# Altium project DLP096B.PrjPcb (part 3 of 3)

## Sheet DLP096B_LED_Driver.SchDoc: LED Driver
size 431 x 279 mm; Date: Not shown in title block; ApprovedBy: Not shown in title block; CheckedBy: Not shown in title block; Author: Not shown in title block; CompanyName: Not shown in title block; DrawnBy: A. Whitehead; Engineer: Not shown in title block; Organization: Not shown in title block; Address1: Not shown in title block; Address2: Not shown in title block; Address3: Not shown in title block; Address4: Not shown in title block; DocumentNumber: 9; Revision: Use project parameter SCH_Rev; SheetNumber: 9; SheetTotal: 10; PageSetup: Record=PageOptions¦CenterHorizontal=True¦CenterVertical=True¦PrintScale=1.00¦XCorrection=1.00¦YCorrection=1.00¦PrintKind=0¦BorderSize=5000000¦LeftOffset=0¦BottomOffset=0¦Orientation=2¦PaperLength=1000¦PaperWidth=1000¦Scale=100¦PaperSource=15¦PrintQuality=600¦MediaType=1¦DitherType=10¦PaperKind=Letter¦PrintScaleMode=1

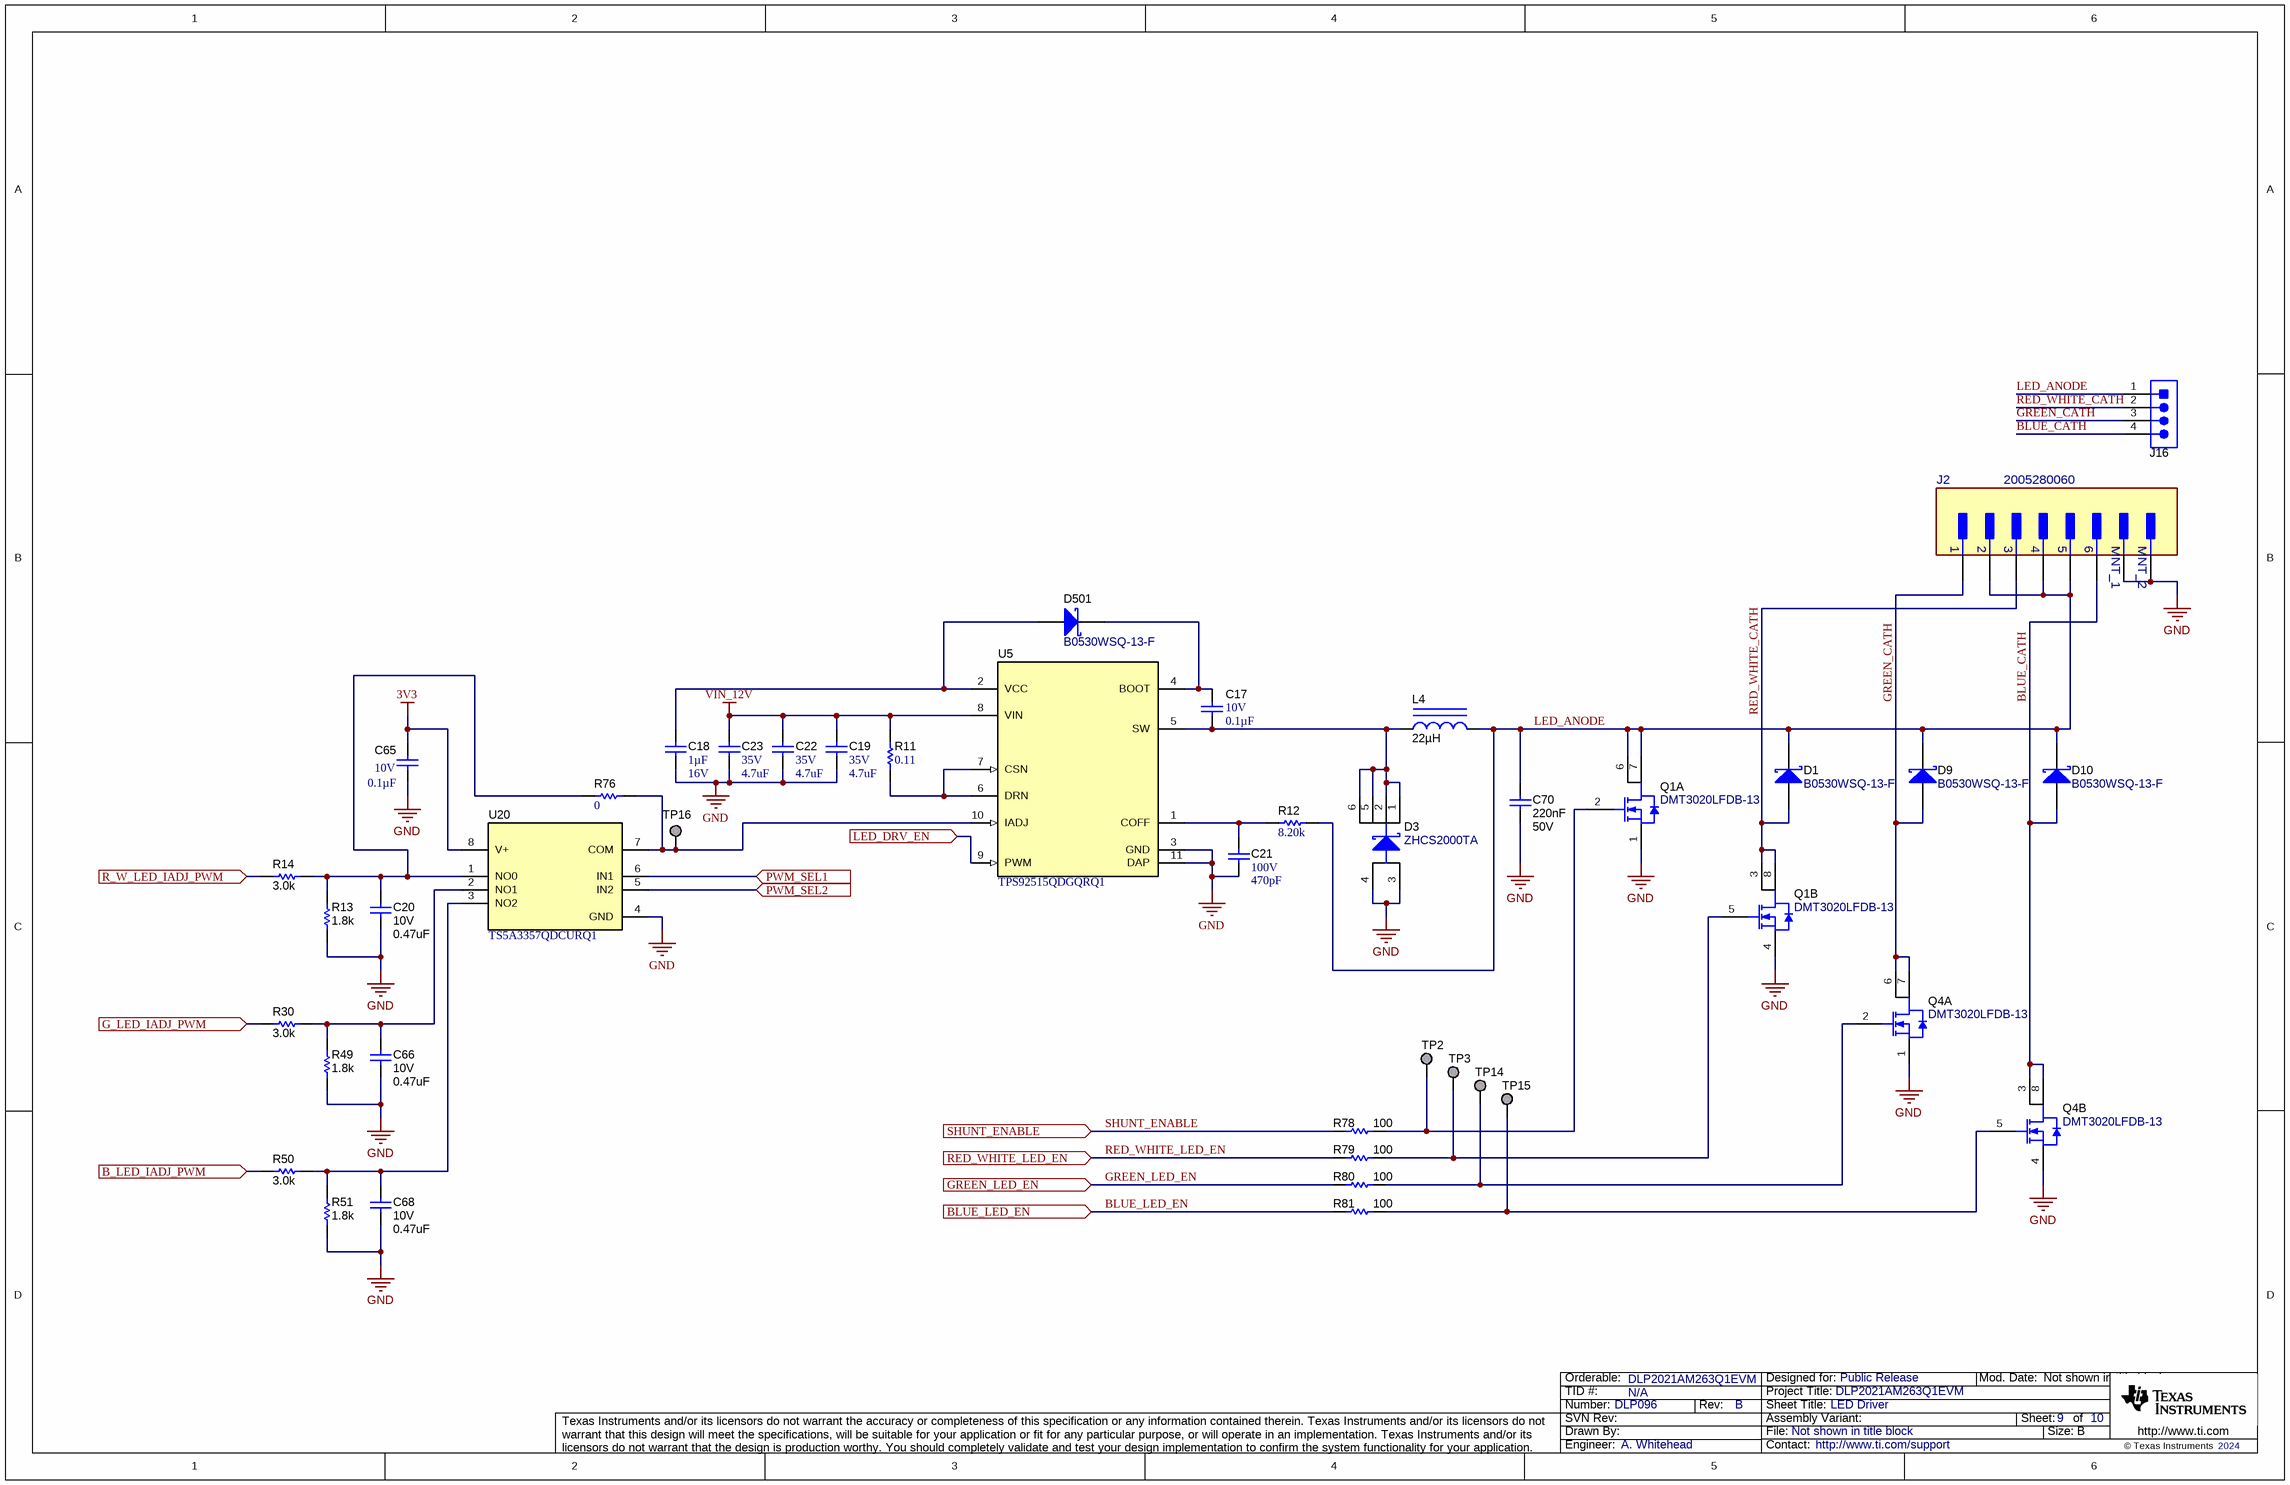
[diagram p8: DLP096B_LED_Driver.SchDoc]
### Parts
C17  VDC_V: 10V  ValueDisplayed: 0.1µF  [0201_033]  (hidden comment: GRM033R61A104KE84D)
C18  Cap_F: 1µF  VDC_V: 16V  [0603]  (hidden comment: CGA3E1X7R1C105K080AC)
C19  VDC_V: 35V  ValueDisplayed: 4.7uF  [0603]  (hidden comment: C1608X5R1V475K080AC)
C20  VDC_V: 10V  ValueDisplayed: 0.47uF  [0402L]  (hidden comment: GRT155R71A474KE01D)
C21  VDC_V: 100V  ValueDisplayed: 470pF  [0603]  (hidden comment: C1608C0G2A471J)
C22  VDC_V: 35V  ValueDisplayed: 4.7uF  [0603]  (hidden comment: C1608X5R1V475K080AC)
C23  VDC_V: 35V  ValueDisplayed: 4.7uF  [0603]  (hidden comment: C1608X5R1V475K080AC)
C65  VDC_V: 10V  ValueDisplayed: 0.1µF  [0402L]  (hidden comment: C0402C104K8RACTU)
C66  VDC_V: 10V  ValueDisplayed: 0.47uF  [0402L]  (hidden comment: GRT155R71A474KE01D)
C68  VDC_V: 10V  ValueDisplayed: 0.47uF  [0402L]  (hidden comment: GRT155R71A474KE01D)
C70  Cap_F: 220nF  VDC_V: 50V  [0603L]  (hidden comment: GCM188R71E104KA57D)
D1  B0530WSQ-13-F  [SOD-323]
D3  ZHCS2000TA  [SOT-26]
D9  B0530WSQ-13-F  [SOD-323]
D10  B0530WSQ-13-F  [SOD-323]
D501  B0530WSQ-13-F  [SOD-323]
J2  2005280060  [FP-2005280060_CONN_11MM2_5MM25-MFG]
J16  TSW-104-07-G-S  [TSW-104-07-G-S]  (value not drawn)
L4  ValueDisplayed: 22µH  [SRN5040TA]  (hidden comment: SRN5040TA-220M)
Q1  DMT3020LFDB-13  [U-DFN2020-6_B]  (parts A,B of 2)
Q4  DMT3020LFDB-13  [U-DFN2020-6_B]  (parts A,B of 2)
R11  ValueDisplayed: 0.11  [1210]  (hidden comment: MCR25JZHFLR110)
R12  ValueDisplayed: 8.20k  [0603]  (hidden comment: RC0603FR-078K2L)
R13  ValueDisplayed: 1.8k  [0402L]  (hidden comment: CRCW04021K80JNED)
R14  ValueDisplayed: 3.0k  [0402L]  (hidden comment: CRCW04023K00JNED)
R30  ValueDisplayed: 3.0k  [0402L]  (hidden comment: CRCW04023K00JNED)
R49  ValueDisplayed: 1.8k  [0402L]  (hidden comment: CRCW04021K80JNED)
R50  ValueDisplayed: 3.0k  [0402L]  (hidden comment: CRCW04023K00JNED)
R51  ValueDisplayed: 1.8k  [0402L]  (hidden comment: CRCW04021K80JNED)
R76  ValueDisplayed: 0  [0402]  (hidden comment: MCR01MZPJ000)
R78  ValueDisplayed: 100  [0402L]  (hidden comment: ERJ-2GEJ101X)
R79  ValueDisplayed: 100  [0402L]  (hidden comment: ERJ-2GEJ101X)
R80  ValueDisplayed: 100  [0402L]  (hidden comment: ERJ-2GEJ101X)
R81  ValueDisplayed: 100  [0402L]  (hidden comment: ERJ-2GEJ101X)
TP2  TP_H0.45P0.75  [TP_H045P075]  (value not drawn)  (no BOM)
TP3  TP_H0.45P0.75  [TP_H045P075]  (value not drawn)  (no BOM)
TP14  TP_H0.45P0.75  [TP_H045P075]  (value not drawn)  (no BOM)
TP15  TP_H0.45P0.75  [TP_H045P075]  (value not drawn)  (no BOM)
TP16  TP_H0.45P0.75  [TP_H045P075]  (value not drawn)  (no BOM)
U5  TPS92515QDGQRQ1  [DGQ0010E_N]
U20  TS5A3357QDCURQ1  [DCU0008A_N]

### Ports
B_LED_IADJ_PWM (in), BLUE_LED_EN (in), G_LED_IADJ_PWM (in), GREEN_LED_EN (in), LED_DRV_EN (in), PWM_SEL1 (in), PWM_SEL2 (in), R_W_LED_IADJ_PWM (in), RED_WHITE_LED_EN (in), SHUNT_ENABLE (in)

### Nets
3V3: C65.1 U20.8(V+)  [project net VDDS33]
GND: C18.2 C19.2 C20.2 C21.2 C22.2 C23.2 C65.2 C66.2 C68.2 C70.2 D3.3(A) D3.4(A) J2.7(MNT_1) J2.8(MNT_2) Q1.1(S1) Q1.4(S2) Q4.1(S1) Q4.4(S2) R13.1 R49.1 R51.1 U5.3(GND) U5.11(DAP) U20.4(GND)
VIN_12V: C19.1 C22.1 C23.1 R11.2 U5.8(VIN)
B_LED_IADJ_PWM: R50.1 ; port B_LED_IADJ_PWM
BLUE_CATH: D10.2(A) J2.6 J16.4 Q4.3(D2) Q4.8(D2)
BLUE_LED_EN: R81.1 ; port BLUE_LED_EN
G_LED_IADJ_PWM: R30.1 ; port G_LED_IADJ_PWM
GREEN_CATH: D9.2(A) J2.1 J16.3 Q4.6(D1) Q4.7(D1)
GREEN_LED_EN: R80.1 ; port GREEN_LED_EN
LED_ANODE: C70.1 D1.1(K) D9.1(K) D10.1(K) J2.2 J2.4 J2.5 J16.1 L4.2 Q1.6(D1) Q1.7(D1) R12.2
LED_DRV_EN: U5.9(PWM) ; port LED_DRV_EN
PWM_SEL1: U20.6(IN1) ; port PWM_SEL1
PWM_SEL2: U20.5(IN2) ; port PWM_SEL2
R_W_LED_IADJ_PWM: R14.1 ; port R_W_LED_IADJ_PWM
RED_WHITE_CATH: D1.2(A) J2.3 J16.2 Q1.3(D2) Q1.8(D2)
RED_WHITE_LED_EN: R79.1 ; port RED_WHITE_LED_EN
SHUNT_ENABLE: R78.1 ; port SHUNT_ENABLE
NetC17_1: C17.1 D501.1(K) U5.4(BOOT)
NetC17_2: C17.2 D3.1(K) D3.2(K) D3.5(K) D3.6(K) L4.1 U5.5(SW)
NetC18_1: C18.1 D501.2(A) U5.2(VCC)
NetC20_1: C20.1 R13.2 R14.2 R76.2 U20.1(NO0)
NetC21_1: C21.1 R12.1 U5.1(COFF)
NetC66_1: C66.1 R30.2 R49.2 U20.2(NO1)
NetC68_1: C68.1 R50.2 R51.2 U20.3(NO2)
NetQ1_2: Q1.2(G1) R78.2 TP2.1
NetQ1_5: Q1.5(G2) R79.2 TP3.1
NetQ4_2: Q4.2(G1) R80.2 TP14.1
NetQ4_5: Q4.5(G2) R81.2 TP15.1
NetR11_1: R11.1 U5.6(DRN) U5.7(CSN)
NetR76_1: R76.1 TP16.1 U5.10(IADJ) U20.7(COM)

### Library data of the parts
C17 = CMP-0086059-1: CAP, CERM, 0.1 µF, 10 V,+/- 10%, X5R, 0201; Manufacturer: MuRata; AEC Category: Q200; Cap_F: 100nF; Value: 0.1uF; SizeY_mm: 0.3; AEC Qualified: N; SizeAreaWB_mm2: 2.08; Cap_Case: 0201; SizeArea_mm2: 0.18; SizeZ_mm: 0.33; SizeX_mm: 0.6; TaMax_C: 85°C; TaMin_C: -55°C; U/M: EA
C18 = CMP-0079607-1: CAP, CERM, 1 µF, 16 V,+/- 10%, X7R, AEC-Q200 Grade 1, 0603; Manufacturer: TDK; TaMin_C: -55°C; Polarized: N; SizeAreaWB_mm2: 4.68; U/M: EA; Value: 1uF; TaMax_C: 125°C; SizeZ_mm: 1; SizeX_mm: 1.6; SizeY_mm: 0.8; SizeArea_mm2: 1.28; AEC Qualified: Y; AEC Category: Q200
C19 C22 C23 = CMP-0007022-5: CAP, CERM, 4.7 uF, 35 V, +/- 10%, X5R, 0603; Manufacturer: TDK; TaMin_C: -55°C; ESR_ohm: 3.728m; Polarized: N; SizeAreaWB_mm2: 4.68; Value1: 0.003728 ohm; U/M: EA; Value: 4.7uF; TaMax_C: 85°C; SizeZ_mm: 1; SizeX_mm: 1.6; SizeY_mm: 0.8; SizeArea_mm2: 1.28; Cap_F: 4.7µF; IRMS_A: 2.6936A; AEC Category: Q200
C20 C66 C68 = CMP-0006350-2: CAP, CERM, 0.47 uF, 10 V, +/- 10%, X7R, AEC-Q200 Grade 1, 0402; Manufacturer: MuRata; TaMin_C: -55°C; Polarized: N; SizeAreaWB_mm2: 3; Value1: Unknown; U/M: EA; Value: 0.1uF; TaMax_C: 125°C; SizeZ_mm: 0.6; SizeX_mm: 1; SizeY_mm: 0.5; Cap_Case: 0402; AEC Qualified: Y; Cap_F: 100nF; AEC Category: Q200
C21 = CMP-0006995-4: CAP, CERM, 470 pF, 100 V, +/- 5%, C0G/NP0, 0603; Manufacturer: TDK; TaMin_C: -55°C; ESR_ohm: 71.4m; Polarized: N; SizeAreaWB_mm2: 4.68; Value1: 0.0714 ohm; U/M: EA; Value: 470pF; TaMax_C: 125°C; SizeZ_mm: 1; SizeX_mm: 1.6; SizeY_mm: 0.8; SizeArea_mm2: 1.28; AEC Category: Q200
C65 = CMP-0078241-1: CAP, CERM, 0.1 µF, 10 V,+/- 10%, X7R, 0402; Manufacturer: Kemet; TaMin_C: -55°C; Polarized: N; SizeAreaWB_mm2: 3; U/M: EA; Value: 0.1uF; TaMax_C: 125°C; SizeZ_mm: 0.6; SizeX_mm: 1; SizeY_mm: 0.5; Cap_Case: 0402; Cap_F: 100nF; AEC Category: Q200
C70 = CMP-0007094-5: CAP, CERM, 0.22 uF, 50 V, +/- 10%, X7R, AEC-Q200 Grade 1, 0603; Manufacturer: TDK; PartNumber: CGA3E3X7R1H224K080AB; TaMin_C: -55°C; ESR_ohm: 0.021699; Polarized: N; SizeAreaWB_mm2: 4.68; Value1: 0.021699 ohm; U/M: EA; Value: 0.22uF; TaMax_C: 125°C; SizeZ_mm: 1; SizeX_mm: 1.6; SizeY_mm: 0.8; Cap_Case: 0603; SizeArea_mm2: 1.28; AEC Qualified: Y; IRMS_A: 1.12496A; AEC Category: Q200
D1 D9 D10 D501 = CMP-0079598-2: Diode, Schottky, 30 V, 0.5 A, AEC-Q101, SOD-323; Manufacturer: Diodes Inc.; SizeAreaWB_mm2: 8.695; Vr_V: 30V; SizeArea_mm2: 3.645; AEC Qualified: Y; TJmax_C: 125°C; AEC Category: Q101; Value: 30V; SizeZ_mm: 1; Io_A: 500mA; Vf_V: 400mV; SizeY_mm: 1.35; Value2: 0.4V; Value1: 0.5A; SizeX_mm: 2.7
D3 = CMP-0028830-2: Diode, Schottky, 40 V, 2 A, AEC-Q101, SOT-26; Manufacturer: Diodes Inc.; SizeZ_mm: 1; Io_A: 2A; AEC Category: Q101; Vr_V: 40V; SizeY_mm: 2.8; Value2: 0.5V; TJmax_C: 125°C; SizeAreaWB_mm2: 13.68; Value: 40V; Green_REACh: Incomplete; AEC Qualified: Y; SizeX_mm: 2.6; SizeArea_mm2: 7.28; Vf_V: 500mV; Green_Lifecycle: Not Set
J2 = CMP-0090189-1: 6 Position FFC, FPC Connector Contacts, Bottom 0.039" (1.00mm) Surface Mount, Right Angle from Molex; Conn Gender: Male; Is Female: yes; DUT-Pitch_mm: 1mm; ContactFinish: Gold,Nickel; SizeZ_mm: 4.15mm; Voltage_V: 125V; AEC Qualified: No; Current_A: 1A
J16 = CMP-0075409-2: Header, 100mil, 4x1, Gold, TH; Manufacturer: Samtec; Pitch_mm: 2.54; Cert_VDE: N; Gender: Male; Cert_CSA: Y; Voltage_V: 550V; Green_REACh: Passed; Current_A: 6.3A; Green_Lifecycle: Active; Row_Count: 1
L4 = CMP-0085685-1: Inductor, Semi-Shielded, Ferrite, 22 µH, 1.5 A, 0.1476 ohm, AEC-Q200 Grade 1, SMD; Manufacturer: Bourns; Irms: 1.5A @ 40C rise; AEC Category: Q200; DCR_ohm: 0.1476; AEC Qualified: Y; SizeArea_mm2: 24.5025; SizeY_mm: 4.95; Isat: 1.62A @ 30% inductance drop; SizeZ_mm: 4.1; SizeAreaWB_mm2: 35.4025; AEC Grade: 1; Value2: 1.5A; Value: 22uH
Q1 Q4 = CMP-0077941-1: MOSFET, 2-CH, N-CH, 30 V, 7.7 A, AEC-Q101, U-DFN2020-6; PartNumber: DMT3020LFDB-7; Manufacturer: Diodes Inc.; Alternate Manufacturer: None; ChType: N; SizeAreaWB_mm2: 9; SizeArea_mm2: 4; IdsMax_A: 7.7A; AEC Qualified: Y; VdsMax_V: 30V; Rdson45_ohm: 0.032; Vgs_V: 20V; AEC Category: Q101; Value: 30V; SizeZ_mm: 0.575; SizeY_mm: 2; Value2: ? nC; U/M: EA; Value1: 0.032 ohm
R11 = CMP-0015168-2: RES, 0.11, 1%, 0.5 W, 1210; Manufacturer: Rohm; Power_W: 500mW; TempCo: 200 ppm/C; SizeAreaWB_mm2: 14.7; Value_Code: R110; U/M: EA; Value: 0.11; EIA_Code: E96; SizeX_mm: 3.2; SizeY_mm: 2.5; SizeZ_mm: 1.35; Value2: 0.5W; SizeArea_mm2: 8; VDC_V: 0V; AEC Category: Q200
R12 = CMP-0023308-5: RES, 8.20 k, 1%, 0.1 W, 0603; Manufacturer: Yageo; Power_W: 100mW; TempCo: 100 ppm/C; Value_Code: 8k20; Value: 8.20k; Res_ohm: 8.2k; SizeX_mm: 1.6; SizeY_mm: 0.8; SizeZ_mm: 1; Value2: 0.1W; SizeArea_mm2: 1.28; AEC Qualified: N; VDC_V: 75V; AEC Category: Q200; SizeAreaWB_mm2: 4.68
R13 R49 R51 = CMP-0026858-5: RES, 1.8 k, 5%, 0.063 W, AEC-Q200 Grade 0, 0402; Manufacturer: Vishay-Dale; Power_W: 63mW; TempCo: 200 ppm/C; Value_Code: 1k80; Value: 1.8k; EIA_Code: E24; SizeX_mm: 1; SizeY_mm: 0.5; SizeZ_mm: 0.6; Value2: 0.063W; AEC Qualified: Y; VDC_V: 50V; AEC Category: Q200; AEC Grade: 0
R14 R30 R50 = CMP-0026917-5: RES, 3.0 k, 5%, 0.063 W, AEC-Q200 Grade 0, 0402; Manufacturer: Vishay-Dale; Power_W: 63mW; TempCo: 200 ppm/C; Value_Code: 3k00; Value: 3.0k; EIA_Code: E24; Res_ohm: 3k; SizeX_mm: 1; SizeY_mm: 0.5; SizeZ_mm: 0.6; Value2: 0.063W; AEC Qualified: Y; VDC_V: 50V; AEC Category: Q200; AEC Grade: 0
R76 = CMP-0027002-2: RES, 0, 5%, 0.063 W, 0402; Manufacturer: Rohm; Power_W: 63mW; TempCo: 500 ppm/C; Value_Code: 0000; U/M: EA; Value: 0; EIA_Code: E24; SizeX_mm: 1; SizeY_mm: 0.5; SizeZ_mm: 0.6; Value2: 0.063W; VDC_V: 50V; AEC Category: Q200
R78-R81 = CMP-0026993-2: RES, 100, 5%, 0.1 W, AEC-Q200 Grade 0, 0402; Manufacturer: Panasonic; Power_W: 100mW; TempCo: 200 ppm/C; Value_Code: 100R; U/M: EA; Value: 100; EIA_Code: E24; SizeX_mm: 1; SizeY_mm: 0.5; SizeZ_mm: 0.6; Value2: 0.1W; AEC Qualified: Y; AEC Grade: 0; AEC Category: Q200
TP2 TP3 TP14-TP16 = CMP-0003719-1: Testpoint; Manufacturer: Texas Instruments; CompType: Pad
U5 = CMP-0073710-1: 2A LED Driver with Integrated NFET, High-Side Current Sense, and Shunt PWM Dimming Capable, DGQ0010E (VSSOP-10); Alternate PartNumber: TPS92515QDGQQ1; Alternate Manufacturer: Texas Instruments; Green_Lifecycle: Active; SizeAreaWB_mm2: 23.52; Green_REACh: Passed; U/M: EA; SizeZ_mm: 1.1; SizeX_mm: 4.88; SizeY_mm: 3.0; SizeArea_mm2: 14.64; CompType: IC
U20 = CMP-0860295-1: Automotive Catalog Single 5-Ohm SP3T Analog Switch 5-V/3.3-V 3:1 Analog Multiplexer/Demultiplexer, DCU0008A (VSSOP-8); Alternate Manufacturer: Texas Instruments; CompType: IC; SizeArea_mm2: 6.4; AEC Category: Q200; SizeZ_mm: 0.9; SizeX_mm: 3.2; SizeY_mm: 2; AEC Qualified: Y; SizeAreaWB_mm2: 12.6

## Sheet DLP096B_Hardware.SchDoc: Hardware
size 431 x 279 mm; Date: Not shown in title block; ApprovedBy: Not shown in title block; CheckedBy: Not shown in title block; Author: Not shown in title block; CompanyName: Not shown in title block; DrawnBy: A. Whitehead; Engineer: Not shown in title block; Organization: Not shown in title block; Address1: Not shown in title block; Address2: Not shown in title block; Address3: Not shown in title block; Address4: Not shown in title block; DocumentNumber: 10; Revision: Use project parameter SCH_Rev; SheetNumber: 10; SheetTotal: 10; PageSetup: Record=PageOptions¦CenterHorizontal=True¦CenterVertical=True¦PrintScale=1.00¦XCorrection=1.00¦YCorrection=1.00¦PrintKind=0¦BorderSize=5000000¦LeftOffset=0¦BottomOffset=0¦Orientation=2¦PaperLength=1000¦PaperWidth=1000¦Scale=100¦PaperSource=15¦PrintQuality=600¦MediaType=1¦DitherType=10¦PaperKind=Letter¦PrintScaleMode=1

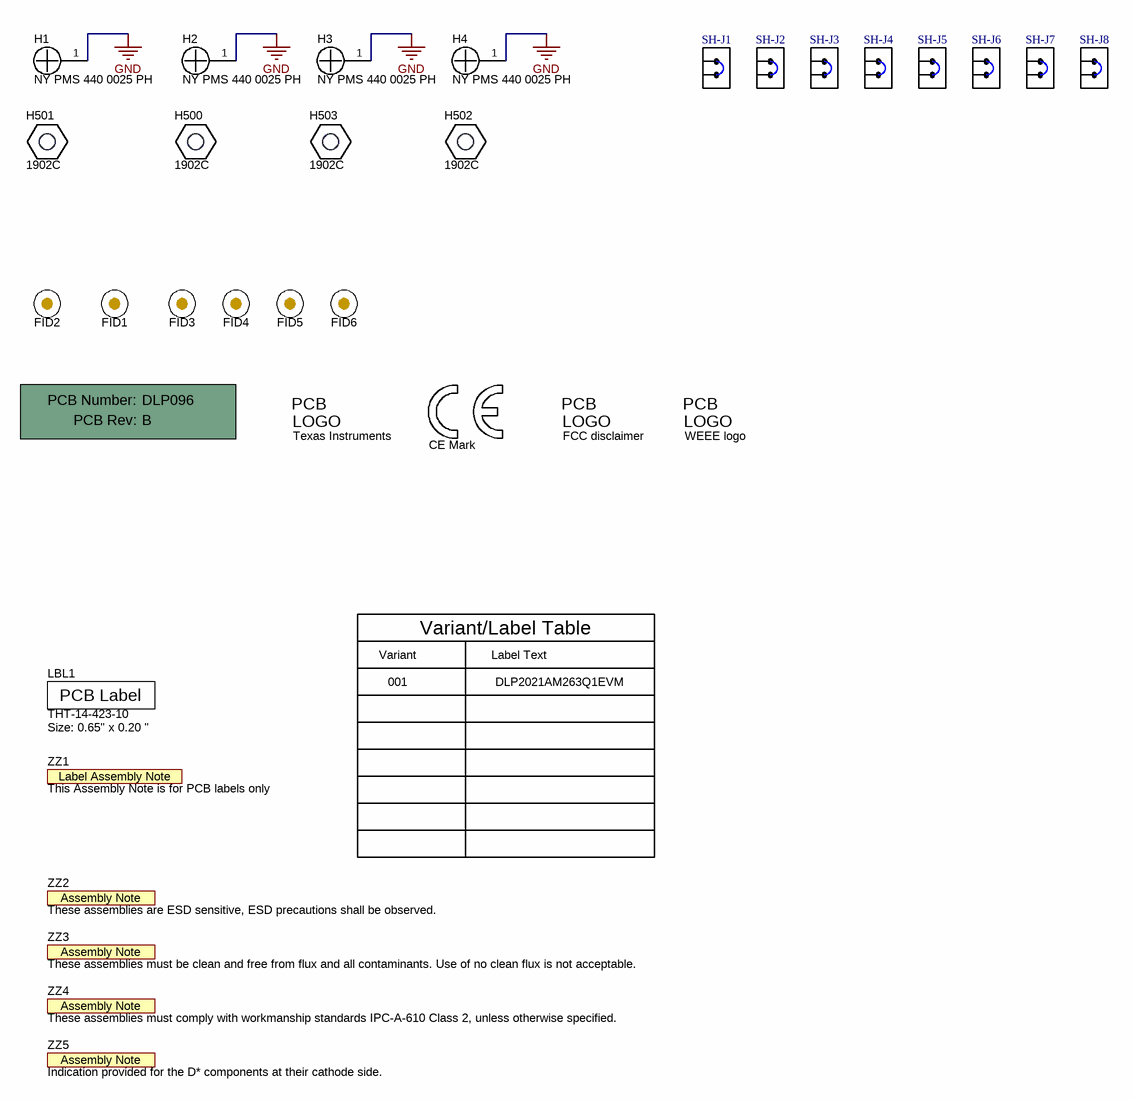
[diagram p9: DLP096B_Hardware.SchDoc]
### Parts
!PCB1  Printed Circuit Board  (value not drawn)  (mechanical)
FID1  Fiducial  [Fiducial10-20]  (value not drawn)
FID2  Fiducial  [Fiducial10-20]  (value not drawn)
FID3  Fiducial  [Fiducial10-20]  (value not drawn)
FID4  Fiducial  [Fiducial10-20]  (value not drawn)
FID5  Fiducial  [Fiducial10-20]  (value not drawn)
FID6  Fiducial  [Fiducial10-20]  (value not drawn)
H1  NY PMS 440 0025 PH  [NY PMS 440 0025 PH]
H2  NY PMS 440 0025 PH  [NY PMS 440 0025 PH]
H3  NY PMS 440 0025 PH  [NY PMS 440 0025 PH]
H4  NY PMS 440 0025 PH  [NY PMS 440 0025 PH]
H500  1902C  [Keystone_1902C]
H501  1902C  [Keystone_1902C]
H502  1902C  [Keystone_1902C]
H503  1902C  [Keystone_1902C]
LBL1  THT-14-423-10  Note: Size: 0.65" x 0.20 "  [Label_650x200]
Logo1  FCC disclaimer  [FCC_disclaimer]  (no BOM)
Logo2  Texas Instruments  [TI_Stacked_Overlay_Small]  (no BOM)
Logo3  WEEE logo  [WEEE_Minimum]  (no BOM)
Logo4  CE Mark  [CE_Mark_5mm]  (no BOM)
SH-J1  M7582-05  [Harwin_M7582-05]  (value not drawn)
SH-J2  M7582-05  [Harwin_M7582-05]  (value not drawn)
SH-J3  M7582-05  [Harwin_M7582-05]  (value not drawn)
SH-J4  M7582-05  [Harwin_M7582-05]  (value not drawn)
SH-J5  M7582-05  [Harwin_M7582-05]  (value not drawn)
SH-J6  M7582-05  [Harwin_M7582-05]  (value not drawn)
SH-J7  M7582-05  [Harwin_M7582-05]  (value not drawn)
SH-J8  M7582-05  [Harwin_M7582-05]  (value not drawn)
ZZ1  This Assembly Note is for PCB labels only  [AssemblyNoteLabel]  (no BOM)
ZZ2  These assemblies are ESD sensitive, ESD precautions shall be observed.  [AssemblyNote]  (no BOM)
ZZ3  These assemblies must be clean and free from flux and all contaminants. Use of no clean flux is not acceptable.  [AssemblyNote]  (no BOM)
ZZ4  These assemblies must comply with workmanship standards IPC-A-610 Class 2, unless otherwise specified.  [AssemblyNote]  (no BOM)
ZZ5  Indication provided for the D* components at their cathode side.  [AssemblyNote]  (no BOM)

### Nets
GND: H1.1 H2.1 H3.1 H4.1

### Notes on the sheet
- Variant
- Variant/Label Table
- Label Text
- 001
- DLP2021AM263Q1EVM

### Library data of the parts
!PCB1 = CMP-0003618-2: Manufacturer: Any; PartNumber: DLP096
FID1-FID6 = CMP-0077181-1: Fiducial mark.  There is nothing to buy or mount.
H1-H4 = CMP-0003617-1: Machine Screw, Round, #4-40 x 1/4, Nylon, Philips panhead; Manufacturer: B&F Fastener Supply; CompType: Hardware
H500-H503 = CMP-0003610-1: Standoff, Hex, 0.5"L #4-40 Nylon; Manufacturer: Keystone; CompType: Hardware
LBL1 = CMP-0003625-1: Thermal Transfer Printable Labels, 0.650" W x 0.200" H - 10,000 per roll; Manufacturer: Brady; CompType: Label
Logo1 = CMP-0074847-1: FCC_disclaimer; Library Reference: Logo
Logo2 = CMP-0074838-1: Texas Instrument Corporate Signature; SymbolCreator: a0412235; Lib Reference: TI_Logo; Library Reference: Logo
Logo3 = CMP-0074769-1
Logo4 = CMP-0074844-1: SymbolCreator: a0412235
SH-J1-SH-J8 = CMP-0078738-1: Single Operation 2.54mm Pitch Open Top Jumper Socket; Manufacturer: Harwin
ZZ1 = CMP-0003616-3
ZZ2 = CMP-0077236-1
ZZ3 = CMP-0077237-1
ZZ4 ZZ5 = CMP-0077238-1

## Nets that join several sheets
5V: DLP096B_System_Power (18 pins), DLP096B_SoC_Power_Clock (R519.2), DLP096B_DMD_Power (C69.1 U22.2), DLP096B_Interfaces_Sockets (J11.4 J11.6 J13.1 J15.1)
DMD_1V8: DLP096B_System_Power (J4.2 TP7.1), DLP096B_DMD_Interface (22 pins)
GND: DLP096B_System_Power (51 pins), DLP096B_SoC_Power_Clock (146 pins), DLP096B_DMD_Power (26 pins), DLP096B_DMD_Interface (42 pins), DLP096B_SoC_Memory (38 pins), DLP096B_Interfaces_Sockets (20 pins), DLP096B_LED_Driver (24 pins), DLP096B_Hardware (H1.1 H2.1 H3.1 H4.1)
VBIAS: DLP096B_DMD_Power (5 pins), DLP096B_DMD_Interface (C64.1 J9.D15)
VDDAR: DLP096B_System_Power (J3.2 R36.2 TP6.1), DLP096B_SoC_Power_Clock (45 pins)
VDDS33: DLP096B_System_Power (12 pins), DLP096B_SoC_Power_Clock (20 pins), DLP096B_DMD_Power (6 pins), DLP096B_DMD_Interface (17 pins), DLP096B_SoC_Memory (38 pins), DLP096B_Interfaces_Sockets (7 pins), DLP096B_LED_Driver (C65.1 U20.8)
VIN_12V: DLP096B_System_Power (9 pins), DLP096B_LED_Driver (5 pins)
VOFFSET: DLP096B_DMD_Power (7 pins), DLP096B_DMD_Interface (C63.1 J9.E14)
VRESET: DLP096B_DMD_Power (6 pins), DLP096B_DMD_Interface (C59.1 J9.D14)
B_LED_IADJ_PWM: DLP096B_Interfaces_Sockets (U12.C2), DLP096B_LED_Driver (R50.1)
BLUE_LED_EN: DLP096B_Interfaces_Sockets (U12.M1), DLP096B_LED_Driver (R81.1)
BROWNOUT_RST: DLP096B_DMD_Power (R77.1 U22.1), DLP096B_Interfaces_Sockets (U12.A10)
DMD_D7: DLP096B_DMD_Interface (U13.10), DLP096B_Interfaces_Sockets (U12.A16)
DMD_INTERFACE_EN: DLP096B_DMD_Interface (6 pins), DLP096B_Interfaces_Sockets (U12.D9)
DMD_POWER_EN: DLP096B_System_Power (U4.C1), DLP096B_DMD_Power (R37.2 TP11.1 U9.24 U14.2), DLP096B_Interfaces_Sockets (U12.A15)
DMD_SAC_CLK: DLP096B_DMD_Interface (U16.10), DLP096B_Interfaces_Sockets (U12.D13)
G_LED_IADJ_PWM: DLP096B_Interfaces_Sockets (U12.D3), DLP096B_LED_Driver (R30.1)
GPMC_BE0n_CLE: DLP096B_DMD_Interface (U12.C18), DLP096B_Interfaces_Sockets (J13.10)
GPMC_WAIT0: DLP096B_DMD_Interface (U12.G18), DLP096B_Interfaces_Sockets (J13.20)
GPMC_WPn: DLP096B_DMD_Interface (U12.G15), DLP096B_Interfaces_Sockets (J13.18)
GREEN_LED_EN: DLP096B_Interfaces_Sockets (U12.L1), DLP096B_LED_Driver (R80.1)
I2C0_SCL: DLP096B_DMD_Interface (R86.1 U21.8), DLP096B_Interfaces_Sockets (J14.6 U12.A13)
I2C0_SDA: DLP096B_DMD_Interface (R85.1 U21.7), DLP096B_Interfaces_Sockets (J14.4 U12.B13)
LED_DRV_EN: DLP096B_Interfaces_Sockets (U12.C9), DLP096B_LED_Driver (U5.9)
PWM_SEL1: DLP096B_Interfaces_Sockets (U12.E2), DLP096B_LED_Driver (U20.6)
PWM_SEL2: DLP096B_Interfaces_Sockets (U12.D1), DLP096B_LED_Driver (U20.5)
R_W_LED_IADJ_PWM: DLP096B_Interfaces_Sockets (U12.B2), DLP096B_LED_Driver (R14.1)
RED_WHITE_LED_EN: DLP096B_Interfaces_Sockets (U12.L2), DLP096B_LED_Driver (R79.1)
SHUNT_ENABLE: DLP096B_Interfaces_Sockets (U12.K1), DLP096B_LED_Driver (R78.1)
SOC_CLOCKOUT0: DLP096B_SoC_Power_Clock (U12.M2), DLP096B_Interfaces_Sockets (J15.12 U12.R17)
Soc_PORz: DLP096B_System_Power (U6.7), DLP096B_SoC_Power_Clock (R73.1 U12.R2), DLP096B_SoC_Memory (R46.2)
SPI0_CLK: DLP096B_SoC_Memory (U18.11), DLP096B_Interfaces_Sockets (J11.7 U12.A11)
SPI0_D0: DLP096B_SoC_Memory (U18.10), DLP096B_Interfaces_Sockets (J11.5 U12.C10)

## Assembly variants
001: not fitted FID1 FID2 FID3 FID4 FID5 FID6 J2 J13 R76 R87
